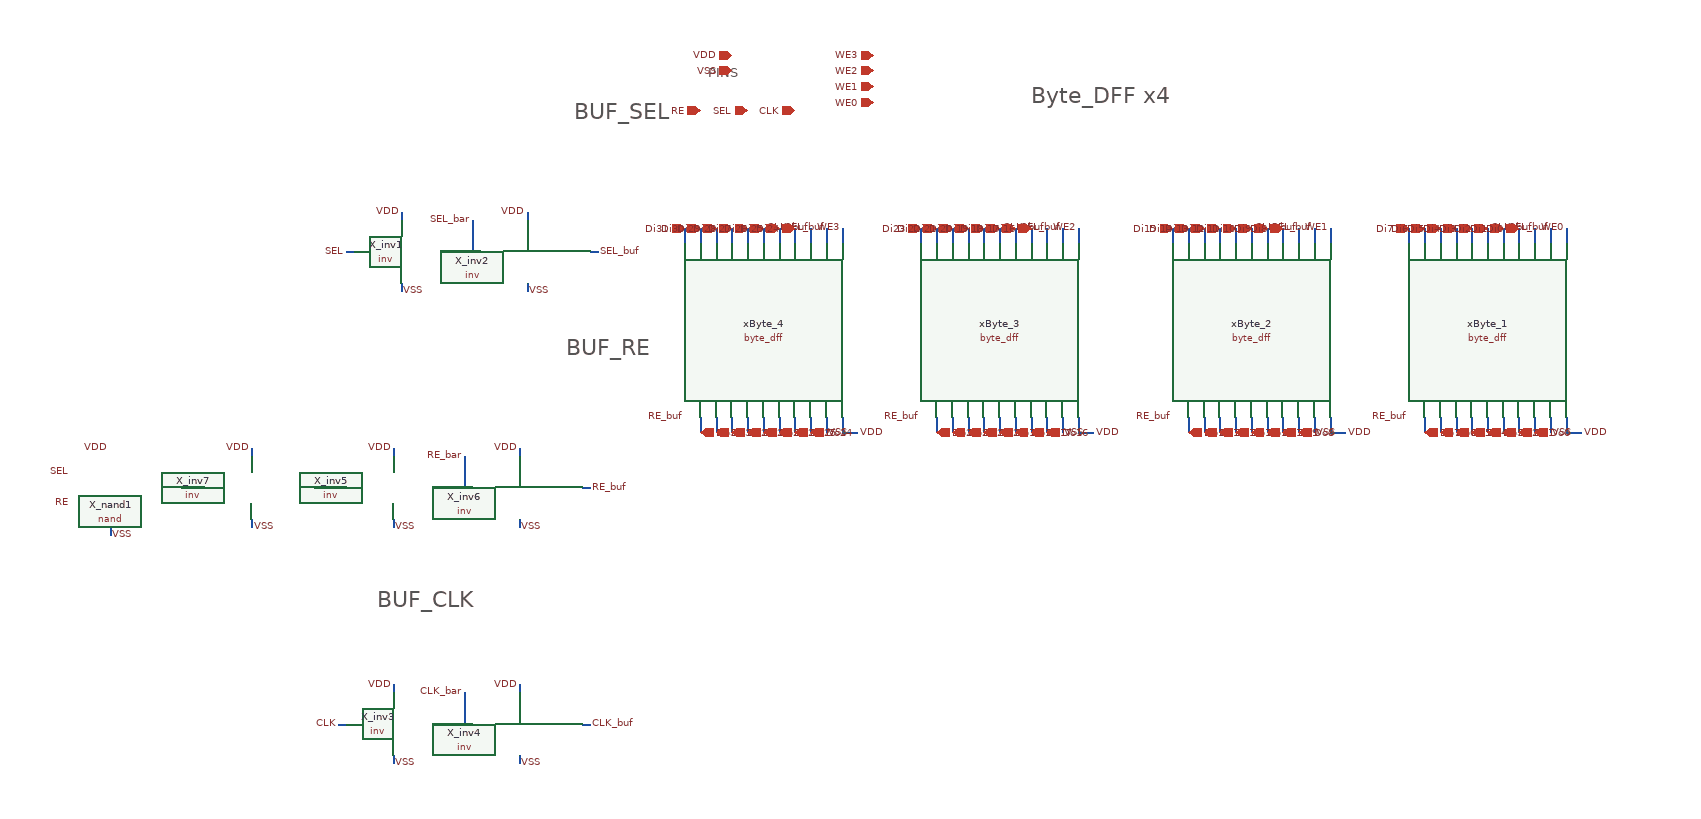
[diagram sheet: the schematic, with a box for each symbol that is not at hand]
v {xschem version=3.0.0 file_version=1.2 }
G {}
K {}
V {}
S {}
E {}
T {Byte_DFF x4} 580 -510 0 0 1 1 {}
T {BUF_CLK} -250 130 0 0 1 1 {}
T {BUF_SEL} 0 -490 0 1 1 1 {}
T {PINS} 170 -540 0 1 0.5 0.5 {}
T {BUF_RE} -10 -190 0 1 1 1 {}
N -140 -300 -120 -300 {
lab=SEL_bar}
N -220 -350 -220 -340 {
lab=VDD}
N -60 -350 -60 -340 {
lab=VDD}
N -220 -260 -220 -250 {
lab=VSS}
N -60 -260 -60 -250 {
lab=VSS}
N -290 -300 -280 -300 {
lab=SEL}
N 20 -300 30 -300 {
lab=SEL_buf}
N 140 -330 140 -310 {
lab=Di31}
N 160 -330 160 -310 {
lab=Di30}
N 180 -330 180 -310 {
lab=Di29}
N 200 -330 200 -310 {
lab=Di28}
N 220 -330 220 -310 {
lab=Di27}
N 240 -330 240 -310 {
lab=Di26}
N 260 -330 260 -310 {
lab=Di25}
N 280 -330 280 -310 {
lab=Di24}
N 300 -330 300 -310 {
lab=CLK_buf}
N 320 -330 320 -310 {
lab=SEL_buf}
N 340 -330 340 -310 {
lab=WE3}
N 160 -90 160 -70 {
lab=Do31}
N 180 -90 180 -70 {
lab=Do30}
N 200 -90 200 -70 {
lab=Do29}
N 220 -90 220 -70 {
lab=Do28}
N 240 -90 240 -70 {
lab=Do27}
N 260 -90 260 -70 {
lab=Do26}
N 280 -90 280 -70 {
lab=Do25}
N 300 -90 300 -70 {
lab=Do24}
N 320 -90 320 -70 {
lab=VSS}
N 340 -90 340 -70 {
lab=VDD}
N 340 -70 360 -70 {
lab=VDD}
N 440 -330 440 -310 {
lab=Di23}
N 460 -330 460 -310 {
lab=Di22}
N 480 -330 480 -310 {
lab=Di21}
N 500 -330 500 -310 {
lab=Di20}
N 520 -330 520 -310 {
lab=Di19}
N 540 -330 540 -310 {
lab=Di18}
N 560 -330 560 -310 {
lab=Di17}
N 580 -330 580 -310 {
lab=Di16}
N 600 -330 600 -310 {
lab=CLK_buf}
N 620 -330 620 -310 {
lab=SEL_buf}
N 640 -330 640 -310 {
lab=WE2}
N 460 -90 460 -70 {
lab=Do23}
N 480 -90 480 -70 {
lab=Do22}
N 500 -90 500 -70 {
lab=Do21}
N 520 -90 520 -70 {
lab=Do20}
N 540 -90 540 -70 {
lab=Do19}
N 560 -90 560 -70 {
lab=Do18}
N 580 -90 580 -70 {
lab=Do17}
N 600 -90 600 -70 {
lab=Do16}
N 620 -90 620 -70 {
lab=VSS}
N 640 -90 640 -70 {
lab=VDD}
N 640 -70 660 -70 {
lab=VDD}
N 760 -330 760 -310 {
lab=Di15}
N 780 -330 780 -310 {
lab=Di14}
N 800 -330 800 -310 {
lab=Di13}
N 820 -330 820 -310 {
lab=Di12}
N 840 -330 840 -310 {
lab=Di11}
N 860 -330 860 -310 {
lab=Di10}
N 880 -330 880 -310 {
lab=Di9}
N 900 -330 900 -310 {
lab=Di8}
N 920 -330 920 -310 {
lab=CLK_buf}
N 940 -330 940 -310 {
lab=SEL_buf}
N 960 -330 960 -310 {
lab=WE1}
N 780 -90 780 -70 {
lab=Do15}
N 800 -90 800 -70 {
lab=Do14}
N 820 -90 820 -70 {
lab=Do13}
N 840 -90 840 -70 {
lab=Do12}
N 860 -90 860 -70 {
lab=Do11}
N 880 -90 880 -70 {
lab=Do10}
N 900 -90 900 -70 {
lab=Do9}
N 920 -90 920 -70 {
lab=Do8}
N 940 -90 940 -70 {
lab=VSS}
N 960 -90 960 -70 {
lab=VDD}
N 960 -70 980 -70 {
lab=VDD}
N 1060 -330 1060 -310 {
lab=Di7}
N 1080 -330 1080 -310 {
lab=Di6}
N 1100 -330 1100 -310 {
lab=Di5}
N 1120 -330 1120 -310 {
lab=Di4}
N 1140 -330 1140 -310 {
lab=Di3}
N 1160 -330 1160 -310 {
lab=Di2}
N 1180 -330 1180 -310 {
lab=Di1}
N 1200 -330 1200 -310 {
lab=Di0}
N 1220 -330 1220 -310 {
lab=CLK_buf}
N 1240 -330 1240 -310 {
lab=SEL_buf}
N 1260 -330 1260 -310 {
lab=WE0}
N 1080 -90 1080 -70 {
lab=Do7}
N 1100 -90 1100 -70 {
lab=Do6}
N 1120 -90 1120 -70 {
lab=Do5}
N 1140 -90 1140 -70 {
lab=Do4}
N 1160 -90 1160 -70 {
lab=Do3}
N 1180 -90 1180 -70 {
lab=Do2}
N 1200 -90 1200 -70 {
lab=Do1}
N 1220 -90 1220 -70 {
lab=Do0}
N 1240 -90 1240 -70 {
lab=VSS}
N 1260 -90 1260 -70 {
lab=VDD}
N 1260 -70 1280 -70 {
lab=VDD}
N -130 -340 -130 -300 {
lab=SEL_bar}
N -150 300 -130 300 {
lab=CLK_bar}
N -230 250 -230 260 {
lab=VDD}
N -70 250 -70 260 {
lab=VDD}
N -230 340 -230 350 {
lab=VSS}
N -70 340 -70 350 {
lab=VSS}
N -300 300 -290 300 {
lab=CLK}
N 10 300 20 300 {
lab=CLK_buf}
N -140 260 -140 300 {
lab=CLK_bar}
N -150 0 -130 0 {
lab=RE_bar}
N -230 -50 -230 -40 {
lab=VDD}
N -70 -50 -70 -40 {
lab=VDD}
N -230 40 -230 50 {
lab=VSS}
N -70 40 -70 50 {
lab=VSS}
N -300 0 -290 0 {
lab=#net1}
N 10 0 20 0 {
lab=RE_buf}
N -140 -40 -140 0 {
lab=RE_bar}
N -500 0 -470 0 {
lab=#net2}
N -330 0 -300 0 {
lab=#net1}
N -590 50 -590 60 {
lab=VSS}
N -410 -50 -410 -40 {
lab=VDD}
N -410 40 -410 50 {
lab=VSS}
C {xschem_lib/DFFRAM_full_custom/byte_dff.sym} 1160 -200 1 0 {name=xByte_1 NF=NF}
C {xschem_lib/DFFRAM_full_custom/inv.sym} -280 -260 0 0 {name=X_inv1 NF=1}
C {xschem_lib/DFFRAM_full_custom/inv.sym} -120 -260 0 0 {name=X_inv2 NF=4}
C {lab_wire.sym} -220 -350 1 0 {name=l1 sig_type=std_logic lab=VDD}
C {lab_wire.sym} -220 -250 2 0 {name=l2 sig_type=std_logic lab=VSS}
C {lab_wire.sym} -60 -350 1 0 {name=l3 sig_type=std_logic lab=VDD}
C {lab_wire.sym} -60 -250 2 0 {name=l4 sig_type=std_logic lab=VSS}
C {lab_wire.sym} 30 -300 2 0 {name=l5 sig_type=std_logic lab=SEL_buf}
C {ipin.sym} 220 -480 0 0 {name=p1 lab=SEL}
C {lab_wire.sym} 360 -70 2 0 {name=l6 sig_type=std_logic lab=VDD}
C {lab_wire.sym} 320 -70 2 0 {name=l7 sig_type=std_logic lab=VSS}
C {lab_wire.sym} 320 -330 1 0 {name=l8 sig_type=std_logic lab=SEL_buf}
C {ipin.sym} 380 -490 0 0 {name=p2 lab=WE0}
C {lab_wire.sym} 340 -330 1 0 {name=l9 sig_type=std_logic lab=WE3}
C {lab_wire.sym} -290 -300 0 0 {name=l10 sig_type=std_logic lab=SEL}
C {lab_wire.sym} 300 -330 1 0 {name=l11 sig_type=std_logic lab=CLK_buf}
C {ipin.sym} 140 -330 1 0 {name=p3 lab=Di31}
C {ipin.sym} 160 -330 1 0 {name=p4 lab=Di30}
C {ipin.sym} 180 -330 1 0 {name=p5 lab=Di29}
C {ipin.sym} 200 -330 1 0 {name=p6 lab=Di28}
C {ipin.sym} 220 -330 1 0 {name=p7 lab=Di27}
C {ipin.sym} 240 -330 1 0 {name=p8 lab=Di26}
C {ipin.sym} 260 -330 1 0 {name=p9 lab=Di25}
C {ipin.sym} 280 -330 1 0 {name=p10 lab=Di24}
C {opin.sym} 160 -70 1 0 {name=p11 lab=Do31}
C {opin.sym} 180 -70 1 0 {name=p12 lab=Do30}
C {opin.sym} 200 -70 1 0 {name=p13 lab=Do29}
C {opin.sym} 220 -70 1 0 {name=p14 lab=Do28}
C {opin.sym} 240 -70 1 0 {name=p15 lab=Do27}
C {opin.sym} 260 -70 1 0 {name=p16 lab=Do26}
C {opin.sym} 280 -70 1 0 {name=p17 lab=Do25}
C {opin.sym} 300 -70 1 0 {name=p18 lab=Do24}
C {iopin.sym} 200 -550 0 0 {name=p19 lab=VDD}
C {iopin.sym} 200 -530 0 0 {name=p20 lab=VSS}
C {xschem_lib/DFFRAM_full_custom/byte_dff.sym} 860 -200 1 0 {name=xByte_2 NF=NF}
C {lab_wire.sym} 660 -70 2 0 {name=l12 sig_type=std_logic lab=VDD}
C {lab_wire.sym} 620 -70 2 0 {name=l13 sig_type=std_logic lab=VSS}
C {lab_wire.sym} 620 -330 1 0 {name=l14 sig_type=std_logic lab=SEL_buf}
C {lab_wire.sym} 640 -330 1 0 {name=l15 sig_type=std_logic lab=WE2}
C {lab_wire.sym} 600 -330 1 0 {name=l16 sig_type=std_logic lab=CLK_buf}
C {ipin.sym} 440 -330 1 0 {name=p21 lab=Di23}
C {ipin.sym} 460 -330 1 0 {name=p22 lab=Di22}
C {ipin.sym} 480 -330 1 0 {name=p23 lab=Di21}
C {ipin.sym} 500 -330 1 0 {name=p24 lab=Di20}
C {ipin.sym} 520 -330 1 0 {name=p25 lab=Di19}
C {ipin.sym} 540 -330 1 0 {name=p26 lab=Di18}
C {ipin.sym} 560 -330 1 0 {name=p27 lab=Di17}
C {ipin.sym} 580 -330 1 0 {name=p28 lab=Di16}
C {opin.sym} 460 -70 1 0 {name=p29 lab=Do23}
C {opin.sym} 480 -70 1 0 {name=p30 lab=Do22}
C {opin.sym} 500 -70 1 0 {name=p31 lab=Do21}
C {opin.sym} 520 -70 1 0 {name=p32 lab=Do20}
C {opin.sym} 540 -70 1 0 {name=p33 lab=Do19}
C {opin.sym} 560 -70 1 0 {name=p34 lab=Do18}
C {opin.sym} 580 -70 1 0 {name=p35 lab=Do17}
C {opin.sym} 600 -70 1 0 {name=p36 lab=Do16}
C {xschem_lib/DFFRAM_full_custom/byte_dff.sym} 540 -200 1 0 {name=xByte_3 NF=NF}
C {lab_wire.sym} 980 -70 2 0 {name=l17 sig_type=std_logic lab=VDD}
C {lab_wire.sym} 940 -70 2 0 {name=l18 sig_type=std_logic lab=VSS}
C {lab_wire.sym} 940 -330 1 0 {name=l19 sig_type=std_logic lab=SEL_buf}
C {lab_wire.sym} 960 -330 1 0 {name=l20 sig_type=std_logic lab=WE1}
C {lab_wire.sym} 920 -330 1 0 {name=l21 sig_type=std_logic lab=CLK_buf}
C {ipin.sym} 760 -330 1 0 {name=p37 lab=Di15}
C {ipin.sym} 780 -330 1 0 {name=p38 lab=Di14}
C {ipin.sym} 800 -330 1 0 {name=p39 lab=Di13}
C {ipin.sym} 820 -330 1 0 {name=p40 lab=Di12}
C {ipin.sym} 840 -330 1 0 {name=p41 lab=Di11}
C {ipin.sym} 860 -330 1 0 {name=p42 lab=Di10}
C {ipin.sym} 880 -330 1 0 {name=p43 lab=Di9}
C {ipin.sym} 900 -330 1 0 {name=p44 lab=Di8}
C {opin.sym} 780 -70 1 0 {name=p45 lab=Do15}
C {opin.sym} 800 -70 1 0 {name=p46 lab=Do14}
C {opin.sym} 820 -70 1 0 {name=p47 lab=Do13}
C {opin.sym} 840 -70 1 0 {name=p48 lab=Do12}
C {opin.sym} 860 -70 1 0 {name=p49 lab=Do11}
C {opin.sym} 880 -70 1 0 {name=p50 lab=Do10}
C {opin.sym} 900 -70 1 0 {name=p51 lab=Do9}
C {opin.sym} 920 -70 1 0 {name=p52 lab=Do8}
C {xschem_lib/DFFRAM_full_custom/byte_dff.sym} 240 -200 1 0 {name=xByte_4 NF=NF}
C {lab_wire.sym} 1280 -70 2 0 {name=l22 sig_type=std_logic lab=VDD}
C {lab_wire.sym} 1240 -70 2 0 {name=l23 sig_type=std_logic lab=VSS}
C {lab_wire.sym} 1240 -330 1 0 {name=l24 sig_type=std_logic lab=SEL_buf}
C {lab_wire.sym} 1260 -330 1 0 {name=l25 sig_type=std_logic lab=WE0}
C {lab_wire.sym} 1220 -330 1 0 {name=l26 sig_type=std_logic lab=CLK_buf}
C {ipin.sym} 1060 -330 1 0 {name=p53 lab=Di7}
C {ipin.sym} 1080 -330 1 0 {name=p54 lab=Di6}
C {ipin.sym} 1100 -330 1 0 {name=p55 lab=Di5}
C {ipin.sym} 1120 -330 1 0 {name=p56 lab=Di4}
C {ipin.sym} 1140 -330 1 0 {name=p57 lab=Di3}
C {ipin.sym} 1160 -330 1 0 {name=p58 lab=Di2}
C {ipin.sym} 1180 -330 1 0 {name=p59 lab=Di1}
C {ipin.sym} 1200 -330 1 0 {name=p60 lab=Di0}
C {opin.sym} 1080 -70 1 0 {name=p61 lab=Do7}
C {opin.sym} 1100 -70 1 0 {name=p62 lab=Do6}
C {opin.sym} 1120 -70 1 0 {name=p63 lab=Do5}
C {opin.sym} 1140 -70 1 0 {name=p64 lab=Do4}
C {opin.sym} 1160 -70 1 0 {name=p65 lab=Do3}
C {opin.sym} 1180 -70 1 0 {name=p66 lab=Do2}
C {opin.sym} 1200 -70 1 0 {name=p67 lab=Do1}
C {opin.sym} 1220 -70 1 0 {name=p68 lab=Do0}
C {ipin.sym} 380 -510 0 0 {name=p69 lab=WE1}
C {ipin.sym} 380 -530 0 0 {name=p70 lab=WE2}
C {ipin.sym} 380 -550 0 0 {name=p71 lab=WE3}
C {ipin.sym} 280 -480 0 0 {name=p72 lab=CLK}
C {lab_wire.sym} -130 -340 1 0 {name=l28 sig_type=std_logic lab=SEL_bar}
C {xschem_lib/DFFRAM_full_custom/inv.sym} -290 340 0 0 {name=X_inv3 NF=2}
C {xschem_lib/DFFRAM_full_custom/inv.sym} -130 340 0 0 {name=X_inv4 NF=8}
C {lab_wire.sym} -230 250 1 0 {name=l34 sig_type=std_logic lab=VDD}
C {lab_wire.sym} -230 350 2 0 {name=l35 sig_type=std_logic lab=VSS}
C {lab_wire.sym} -70 250 1 0 {name=l36 sig_type=std_logic lab=VDD}
C {lab_wire.sym} -70 350 2 0 {name=l37 sig_type=std_logic lab=VSS}
C {lab_wire.sym} 20 300 2 0 {name=l38 sig_type=std_logic lab=CLK_buf}
C {lab_wire.sym} -300 300 0 0 {name=l39 sig_type=std_logic lab=CLK}
C {lab_wire.sym} -140 260 1 0 {name=l40 sig_type=std_logic lab=CLK_bar}
C {xschem_lib/DFFRAM_full_custom/inv.sym} -290 40 0 0 {name=X_inv5 NF=NF*3}
C {xschem_lib/DFFRAM_full_custom/inv.sym} -130 40 0 0 {name=X_inv6 NF=NF*9}
C {lab_wire.sym} -230 -50 1 0 {name=l27 sig_type=std_logic lab=VDD}
C {lab_wire.sym} -230 50 2 0 {name=l29 sig_type=std_logic lab=VSS}
C {lab_wire.sym} -70 -50 1 0 {name=l30 sig_type=std_logic lab=VDD}
C {lab_wire.sym} -70 50 2 0 {name=l31 sig_type=std_logic lab=VSS}
C {lab_wire.sym} 20 0 2 0 {name=l32 sig_type=std_logic lab=RE_buf}
C {lab_wire.sym} -640 20 0 0 {name=l33 sig_type=std_logic lab=RE}
C {lab_wire.sym} -140 -40 1 0 {name=l41 sig_type=std_logic lab=RE_bar}
C {lab_wire.sym} 140 -90 3 0 {name=l42 sig_type=std_logic lab=RE_buf}
C {lab_wire.sym} 440 -90 3 0 {name=l43 sig_type=std_logic lab=RE_buf}
C {lab_wire.sym} 760 -90 3 0 {name=l44 sig_type=std_logic lab=RE_buf}
C {lab_wire.sym} 1060 -90 3 0 {name=l45 sig_type=std_logic lab=RE_buf}
C {ipin.sym} 160 -480 0 0 {name=p73 lab=RE}
C {xschem_lib/DFFRAM_full_custom/nand.sym} -620 30 0 0 {name=X_nand1 NF=1}
C {xschem_lib/DFFRAM_full_custom/inv.sym} -470 40 0 0 {name=X_inv7 NF=NF}
C {lab_wire.sym} -640 -20 0 0 {name=l46 sig_type=std_logic lab=SEL}
C {lab_wire.sym} -590 -50 1 0 {name=l47 sig_type=std_logic lab=VDD}
C {lab_wire.sym} -590 60 2 0 {name=l48 sig_type=std_logic lab=VSS}
C {lab_wire.sym} -410 -50 1 0 {name=l49 sig_type=std_logic lab=VDD}
C {lab_wire.sym} -410 50 2 0 {name=l50 sig_type=std_logic lab=VSS}
